VERSION 5.8 ;
BUSBITCHARS "[]" ;
DIVIDERCHAR "/" ;
UNITS
    DATABASE MICRONS 1000 ;
END UNITS

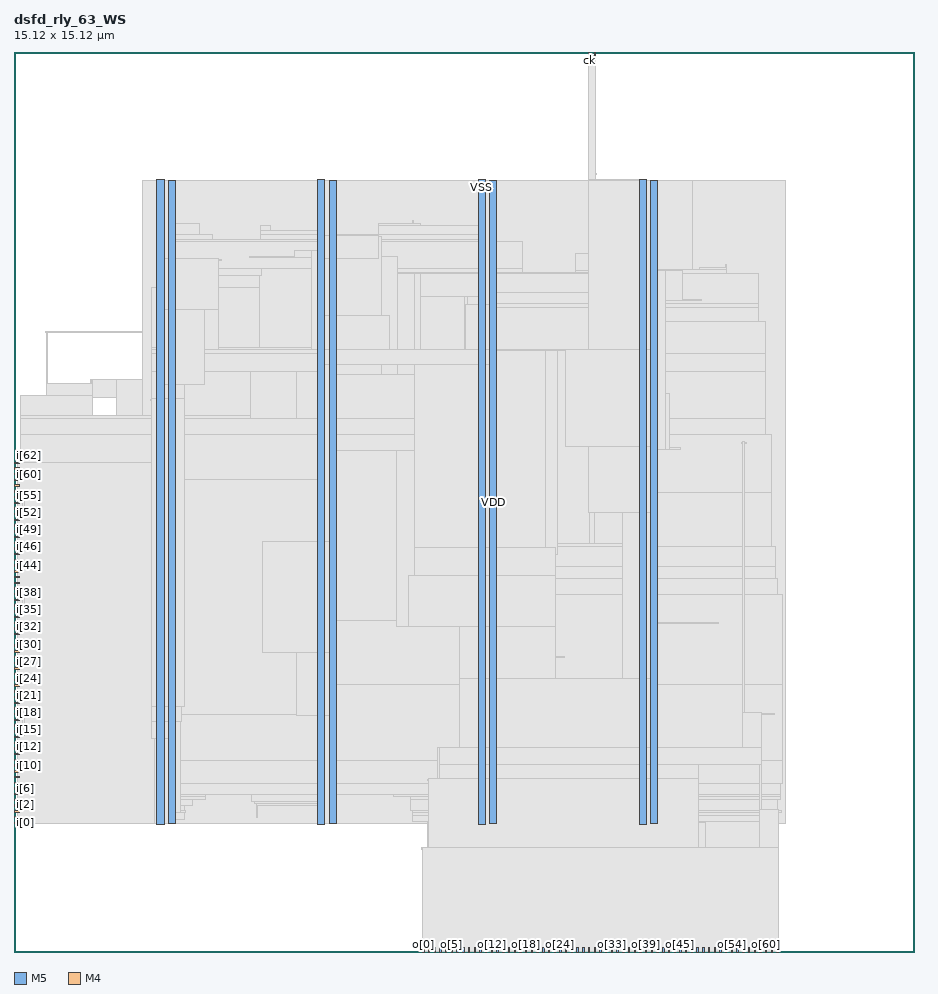
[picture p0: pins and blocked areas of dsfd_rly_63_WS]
MACRO dsfd_rly_63_WS
  FOREIGN dsfd_rly_63_WS 0 0 ;
  CLASS BLOCK ;
  SIZE 15.12 BY 15.12 ;
  PIN ck
    DIRECTION INPUT ;
    USE SIGNAL ;
    PORT
      LAYER M5 ;
        RECT  9.648 15.036 9.672 15.12 ;
    END
  END ck
  PIN i[0]
    DIRECTION INPUT ;
    USE SIGNAL ;
    PORT
      LAYER M4 ;
        RECT  0 2.16 0.084 2.184 ;
    END
  END i[0]
  PIN i[10]
    DIRECTION INPUT ;
    USE SIGNAL ;
    PORT
      LAYER M4 ;
        RECT  0 3.12 0.084 3.144 ;
    END
  END i[10]
  PIN i[11]
    DIRECTION INPUT ;
    USE SIGNAL ;
    PORT
      LAYER M4 ;
        RECT  0 3.216 0.084 3.24 ;
    END
  END i[11]
  PIN i[12]
    DIRECTION INPUT ;
    USE SIGNAL ;
    PORT
      LAYER M4 ;
        RECT  0 3.312 0.084 3.336 ;
    END
  END i[12]
  PIN i[13]
    DIRECTION INPUT ;
    USE SIGNAL ;
    PORT
      LAYER M4 ;
        RECT  0 3.408 0.084 3.432 ;
    END
  END i[13]
  PIN i[14]
    DIRECTION INPUT ;
    USE SIGNAL ;
    PORT
      LAYER M4 ;
        RECT  0 3.504 0.084 3.528 ;
    END
  END i[14]
  PIN i[15]
    DIRECTION INPUT ;
    USE SIGNAL ;
    PORT
      LAYER M4 ;
        RECT  0 3.6 0.084 3.624 ;
    END
  END i[15]
  PIN i[16]
    DIRECTION INPUT ;
    USE SIGNAL ;
    PORT
      LAYER M4 ;
        RECT  0 3.696 0.084 3.72 ;
    END
  END i[16]
  PIN i[17]
    DIRECTION INPUT ;
    USE SIGNAL ;
    PORT
      LAYER M4 ;
        RECT  0 3.792 0.084 3.816 ;
    END
  END i[17]
  PIN i[18]
    DIRECTION INPUT ;
    USE SIGNAL ;
    PORT
      LAYER M4 ;
        RECT  0 3.888 0.084 3.912 ;
    END
  END i[18]
  PIN i[19]
    DIRECTION INPUT ;
    USE SIGNAL ;
    PORT
      LAYER M4 ;
        RECT  0 3.984 0.084 4.008 ;
    END
  END i[19]
  PIN i[1]
    DIRECTION INPUT ;
    USE SIGNAL ;
    PORT
      LAYER M4 ;
        RECT  0 2.256 0.084 2.28 ;
    END
  END i[1]
  PIN i[20]
    DIRECTION INPUT ;
    USE SIGNAL ;
    PORT
      LAYER M4 ;
        RECT  0 4.08 0.084 4.104 ;
    END
  END i[20]
  PIN i[21]
    DIRECTION INPUT ;
    USE SIGNAL ;
    PORT
      LAYER M4 ;
        RECT  0 4.176 0.084 4.2 ;
    END
  END i[21]
  PIN i[22]
    DIRECTION INPUT ;
    USE SIGNAL ;
    PORT
      LAYER M4 ;
        RECT  0 4.272 0.084 4.296 ;
    END
  END i[22]
  PIN i[23]
    DIRECTION INPUT ;
    USE SIGNAL ;
    PORT
      LAYER M4 ;
        RECT  0 4.368 0.084 4.392 ;
    END
  END i[23]
  PIN i[24]
    DIRECTION INPUT ;
    USE SIGNAL ;
    PORT
      LAYER M4 ;
        RECT  0 4.464 0.084 4.488 ;
    END
  END i[24]
  PIN i[25]
    DIRECTION INPUT ;
    USE SIGNAL ;
    PORT
      LAYER M4 ;
        RECT  0 4.56 0.084 4.584 ;
    END
  END i[25]
  PIN i[26]
    DIRECTION INPUT ;
    USE SIGNAL ;
    PORT
      LAYER M4 ;
        RECT  0 4.656 0.084 4.68 ;
    END
  END i[26]
  PIN i[27]
    DIRECTION INPUT ;
    USE SIGNAL ;
    PORT
      LAYER M4 ;
        RECT  0 4.752 0.084 4.776 ;
    END
  END i[27]
  PIN i[28]
    DIRECTION INPUT ;
    USE SIGNAL ;
    PORT
      LAYER M4 ;
        RECT  0 4.848 0.084 4.872 ;
    END
  END i[28]
  PIN i[29]
    DIRECTION INPUT ;
    USE SIGNAL ;
    PORT
      LAYER M4 ;
        RECT  0 4.944 0.084 4.968 ;
    END
  END i[29]
  PIN i[2]
    DIRECTION INPUT ;
    USE SIGNAL ;
    PORT
      LAYER M4 ;
        RECT  0 2.352 0.084 2.376 ;
    END
  END i[2]
  PIN i[30]
    DIRECTION INPUT ;
    USE SIGNAL ;
    PORT
      LAYER M4 ;
        RECT  0 5.04 0.084 5.064 ;
    END
  END i[30]
  PIN i[31]
    DIRECTION INPUT ;
    USE SIGNAL ;
    PORT
      LAYER M4 ;
        RECT  0 5.136 0.084 5.16 ;
    END
  END i[31]
  PIN i[32]
    DIRECTION INPUT ;
    USE SIGNAL ;
    PORT
      LAYER M4 ;
        RECT  0 5.328 0.084 5.352 ;
    END
  END i[32]
  PIN i[33]
    DIRECTION INPUT ;
    USE SIGNAL ;
    PORT
      LAYER M4 ;
        RECT  0 5.424 0.084 5.448 ;
    END
  END i[33]
  PIN i[34]
    DIRECTION INPUT ;
    USE SIGNAL ;
    PORT
      LAYER M4 ;
        RECT  0 5.52 0.084 5.544 ;
    END
  END i[34]
  PIN i[35]
    DIRECTION INPUT ;
    USE SIGNAL ;
    PORT
      LAYER M4 ;
        RECT  0 5.616 0.084 5.64 ;
    END
  END i[35]
  PIN i[36]
    DIRECTION INPUT ;
    USE SIGNAL ;
    PORT
      LAYER M4 ;
        RECT  0 5.712 0.084 5.736 ;
    END
  END i[36]
  PIN i[37]
    DIRECTION INPUT ;
    USE SIGNAL ;
    PORT
      LAYER M4 ;
        RECT  0 5.808 0.084 5.832 ;
    END
  END i[37]
  PIN i[38]
    DIRECTION INPUT ;
    USE SIGNAL ;
    PORT
      LAYER M4 ;
        RECT  0 5.904 0.084 5.928 ;
    END
  END i[38]
  PIN i[39]
    DIRECTION INPUT ;
    USE SIGNAL ;
    PORT
      LAYER M4 ;
        RECT  0 6 0.084 6.024 ;
    END
  END i[39]
  PIN i[3]
    DIRECTION INPUT ;
    USE SIGNAL ;
    PORT
      LAYER M4 ;
        RECT  0 2.448 0.084 2.472 ;
    END
  END i[3]
  PIN i[40]
    DIRECTION INPUT ;
    USE SIGNAL ;
    PORT
      LAYER M4 ;
        RECT  0 6.096 0.084 6.12 ;
    END
  END i[40]
  PIN i[41]
    DIRECTION INPUT ;
    USE SIGNAL ;
    PORT
      LAYER M4 ;
        RECT  0 6.192 0.084 6.216 ;
    END
  END i[41]
  PIN i[42]
    DIRECTION INPUT ;
    USE SIGNAL ;
    PORT
      LAYER M4 ;
        RECT  0 6.288 0.084 6.312 ;
    END
  END i[42]
  PIN i[43]
    DIRECTION INPUT ;
    USE SIGNAL ;
    PORT
      LAYER M4 ;
        RECT  0 6.384 0.084 6.408 ;
    END
  END i[43]
  PIN i[44]
    DIRECTION INPUT ;
    USE SIGNAL ;
    PORT
      LAYER M4 ;
        RECT  0 6.48 0.084 6.504 ;
    END
  END i[44]
  PIN i[45]
    DIRECTION INPUT ;
    USE SIGNAL ;
    PORT
      LAYER M4 ;
        RECT  0 6.576 0.084 6.6 ;
    END
  END i[45]
  PIN i[46]
    DIRECTION INPUT ;
    USE SIGNAL ;
    PORT
      LAYER M4 ;
        RECT  0 6.672 0.084 6.696 ;
    END
  END i[46]
  PIN i[47]
    DIRECTION INPUT ;
    USE SIGNAL ;
    PORT
      LAYER M4 ;
        RECT  0 6.768 0.084 6.792 ;
    END
  END i[47]
  PIN i[48]
    DIRECTION INPUT ;
    USE SIGNAL ;
    PORT
      LAYER M4 ;
        RECT  0 6.864 0.084 6.888 ;
    END
  END i[48]
  PIN i[49]
    DIRECTION INPUT ;
    USE SIGNAL ;
    PORT
      LAYER M4 ;
        RECT  0 6.96 0.084 6.984 ;
    END
  END i[49]
  PIN i[4]
    DIRECTION INPUT ;
    USE SIGNAL ;
    PORT
      LAYER M4 ;
        RECT  0 2.544 0.084 2.568 ;
    END
  END i[4]
  PIN i[50]
    DIRECTION INPUT ;
    USE SIGNAL ;
    PORT
      LAYER M4 ;
        RECT  0 7.056 0.084 7.08 ;
    END
  END i[50]
  PIN i[51]
    DIRECTION INPUT ;
    USE SIGNAL ;
    PORT
      LAYER M4 ;
        RECT  0 7.152 0.084 7.176 ;
    END
  END i[51]
  PIN i[52]
    DIRECTION INPUT ;
    USE SIGNAL ;
    PORT
      LAYER M4 ;
        RECT  0 7.248 0.084 7.272 ;
    END
  END i[52]
  PIN i[53]
    DIRECTION INPUT ;
    USE SIGNAL ;
    PORT
      LAYER M4 ;
        RECT  0 7.344 0.084 7.368 ;
    END
  END i[53]
  PIN i[54]
    DIRECTION INPUT ;
    USE SIGNAL ;
    PORT
      LAYER M4 ;
        RECT  0 7.44 0.084 7.464 ;
    END
  END i[54]
  PIN i[55]
    DIRECTION INPUT ;
    USE SIGNAL ;
    PORT
      LAYER M4 ;
        RECT  0 7.536 0.084 7.56 ;
    END
  END i[55]
  PIN i[56]
    DIRECTION INPUT ;
    USE SIGNAL ;
    PORT
      LAYER M4 ;
        RECT  0 7.632 0.084 7.656 ;
    END
  END i[56]
  PIN i[57]
    DIRECTION INPUT ;
    USE SIGNAL ;
    PORT
      LAYER M4 ;
        RECT  0 7.728 0.084 7.752 ;
    END
  END i[57]
  PIN i[58]
    DIRECTION INPUT ;
    USE SIGNAL ;
    PORT
      LAYER M4 ;
        RECT  0 7.824 0.084 7.848 ;
    END
  END i[58]
  PIN i[59]
    DIRECTION INPUT ;
    USE SIGNAL ;
    PORT
      LAYER M4 ;
        RECT  0 7.92 0.084 7.944 ;
    END
  END i[59]
  PIN i[5]
    DIRECTION INPUT ;
    USE SIGNAL ;
    PORT
      LAYER M4 ;
        RECT  0 2.64 0.084 2.664 ;
    END
  END i[5]
  PIN i[60]
    DIRECTION INPUT ;
    USE SIGNAL ;
    PORT
      LAYER M4 ;
        RECT  0 8.016 0.084 8.04 ;
    END
  END i[60]
  PIN i[61]
    DIRECTION INPUT ;
    USE SIGNAL ;
    PORT
      LAYER M4 ;
        RECT  0 8.112 0.084 8.136 ;
    END
  END i[61]
  PIN i[62]
    DIRECTION INPUT ;
    USE SIGNAL ;
    PORT
      LAYER M4 ;
        RECT  0 8.208 0.084 8.232 ;
    END
  END i[62]
  PIN i[6]
    DIRECTION INPUT ;
    USE SIGNAL ;
    PORT
      LAYER M4 ;
        RECT  0 2.736 0.084 2.76 ;
    END
  END i[6]
  PIN i[7]
    DIRECTION INPUT ;
    USE SIGNAL ;
    PORT
      LAYER M4 ;
        RECT  0 2.832 0.084 2.856 ;
    END
  END i[7]
  PIN i[8]
    DIRECTION INPUT ;
    USE SIGNAL ;
    PORT
      LAYER M4 ;
        RECT  0 2.928 0.084 2.952 ;
    END
  END i[8]
  PIN i[9]
    DIRECTION INPUT ;
    USE SIGNAL ;
    PORT
      LAYER M4 ;
        RECT  0 3.024 0.084 3.048 ;
    END
  END i[9]
  PIN o[0]
    DIRECTION OUTPUT ;
    USE SIGNAL ;
    PORT
      LAYER M5 ;
        RECT  6.864 0 6.888 0.084 ;
    END
  END o[0]
  PIN o[10]
    DIRECTION OUTPUT ;
    USE SIGNAL ;
    PORT
      LAYER M5 ;
        RECT  7.824 0 7.848 0.084 ;
    END
  END o[10]
  PIN o[11]
    DIRECTION OUTPUT ;
    USE SIGNAL ;
    PORT
      LAYER M5 ;
        RECT  7.92 0 7.944 0.084 ;
    END
  END o[11]
  PIN o[12]
    DIRECTION OUTPUT ;
    USE SIGNAL ;
    PORT
      LAYER M5 ;
        RECT  8.016 0 8.04 0.084 ;
    END
  END o[12]
  PIN o[13]
    DIRECTION OUTPUT ;
    USE SIGNAL ;
    PORT
      LAYER M5 ;
        RECT  8.112 0 8.136 0.084 ;
    END
  END o[13]
  PIN o[14]
    DIRECTION OUTPUT ;
    USE SIGNAL ;
    PORT
      LAYER M5 ;
        RECT  8.208 0 8.232 0.084 ;
    END
  END o[14]
  PIN o[15]
    DIRECTION OUTPUT ;
    USE SIGNAL ;
    PORT
      LAYER M5 ;
        RECT  8.304 0 8.328 0.084 ;
    END
  END o[15]
  PIN o[16]
    DIRECTION OUTPUT ;
    USE SIGNAL ;
    PORT
      LAYER M5 ;
        RECT  8.4 0 8.424 0.084 ;
    END
  END o[16]
  PIN o[17]
    DIRECTION OUTPUT ;
    USE SIGNAL ;
    PORT
      LAYER M5 ;
        RECT  8.496 0 8.52 0.084 ;
    END
  END o[17]
  PIN o[18]
    DIRECTION OUTPUT ;
    USE SIGNAL ;
    PORT
      LAYER M5 ;
        RECT  8.592 0 8.616 0.084 ;
    END
  END o[18]
  PIN o[19]
    DIRECTION OUTPUT ;
    USE SIGNAL ;
    PORT
      LAYER M5 ;
        RECT  8.688 0 8.712 0.084 ;
    END
  END o[19]
  PIN o[1]
    DIRECTION OUTPUT ;
    USE SIGNAL ;
    PORT
      LAYER M5 ;
        RECT  6.96 0 6.984 0.084 ;
    END
  END o[1]
  PIN o[20]
    DIRECTION OUTPUT ;
    USE SIGNAL ;
    PORT
      LAYER M5 ;
        RECT  8.784 0 8.808 0.084 ;
    END
  END o[20]
  PIN o[21]
    DIRECTION OUTPUT ;
    USE SIGNAL ;
    PORT
      LAYER M5 ;
        RECT  8.88 0 8.904 0.084 ;
    END
  END o[21]
  PIN o[22]
    DIRECTION OUTPUT ;
    USE SIGNAL ;
    PORT
      LAYER M5 ;
        RECT  8.976 0 9 0.084 ;
    END
  END o[22]
  PIN o[23]
    DIRECTION OUTPUT ;
    USE SIGNAL ;
    PORT
      LAYER M5 ;
        RECT  9.072 0 9.096 0.084 ;
    END
  END o[23]
  PIN o[24]
    DIRECTION OUTPUT ;
    USE SIGNAL ;
    PORT
      LAYER M5 ;
        RECT  9.168 0 9.192 0.084 ;
    END
  END o[24]
  PIN o[25]
    DIRECTION OUTPUT ;
    USE SIGNAL ;
    PORT
      LAYER M5 ;
        RECT  9.264 0 9.288 0.084 ;
    END
  END o[25]
  PIN o[26]
    DIRECTION OUTPUT ;
    USE SIGNAL ;
    PORT
      LAYER M5 ;
        RECT  9.36 0 9.384 0.084 ;
    END
  END o[26]
  PIN o[27]
    DIRECTION OUTPUT ;
    USE SIGNAL ;
    PORT
      LAYER M5 ;
        RECT  9.456 0 9.48 0.084 ;
    END
  END o[27]
  PIN o[28]
    DIRECTION OUTPUT ;
    USE SIGNAL ;
    PORT
      LAYER M5 ;
        RECT  9.552 0 9.576 0.084 ;
    END
  END o[28]
  PIN o[29]
    DIRECTION OUTPUT ;
    USE SIGNAL ;
    PORT
      LAYER M5 ;
        RECT  9.648 0 9.672 0.084 ;
    END
  END o[29]
  PIN o[2]
    DIRECTION OUTPUT ;
    USE SIGNAL ;
    PORT
      LAYER M5 ;
        RECT  7.056 0 7.08 0.084 ;
    END
  END o[2]
  PIN o[30]
    DIRECTION OUTPUT ;
    USE SIGNAL ;
    PORT
      LAYER M5 ;
        RECT  9.744 0 9.768 0.084 ;
    END
  END o[30]
  PIN o[31]
    DIRECTION OUTPUT ;
    USE SIGNAL ;
    PORT
      LAYER M5 ;
        RECT  9.84 0 9.864 0.084 ;
    END
  END o[31]
  PIN o[32]
    DIRECTION OUTPUT ;
    USE SIGNAL ;
    PORT
      LAYER M5 ;
        RECT  9.936 0 9.96 0.084 ;
    END
  END o[32]
  PIN o[33]
    DIRECTION OUTPUT ;
    USE SIGNAL ;
    PORT
      LAYER M5 ;
        RECT  10.032 0 10.056 0.084 ;
    END
  END o[33]
  PIN o[34]
    DIRECTION OUTPUT ;
    USE SIGNAL ;
    PORT
      LAYER M5 ;
        RECT  10.128 0 10.152 0.084 ;
    END
  END o[34]
  PIN o[35]
    DIRECTION OUTPUT ;
    USE SIGNAL ;
    PORT
      LAYER M5 ;
        RECT  10.224 0 10.248 0.084 ;
    END
  END o[35]
  PIN o[36]
    DIRECTION OUTPUT ;
    USE SIGNAL ;
    PORT
      LAYER M5 ;
        RECT  10.32 0 10.344 0.084 ;
    END
  END o[36]
  PIN o[37]
    DIRECTION OUTPUT ;
    USE SIGNAL ;
    PORT
      LAYER M5 ;
        RECT  10.416 0 10.44 0.084 ;
    END
  END o[37]
  PIN o[38]
    DIRECTION OUTPUT ;
    USE SIGNAL ;
    PORT
      LAYER M5 ;
        RECT  10.512 0 10.536 0.084 ;
    END
  END o[38]
  PIN o[39]
    DIRECTION OUTPUT ;
    USE SIGNAL ;
    PORT
      LAYER M5 ;
        RECT  10.608 0 10.632 0.084 ;
    END
  END o[39]
  PIN o[3]
    DIRECTION OUTPUT ;
    USE SIGNAL ;
    PORT
      LAYER M5 ;
        RECT  7.152 0 7.176 0.084 ;
    END
  END o[3]
  PIN o[40]
    DIRECTION OUTPUT ;
    USE SIGNAL ;
    PORT
      LAYER M5 ;
        RECT  10.704 0 10.728 0.084 ;
    END
  END o[40]
  PIN o[41]
    DIRECTION OUTPUT ;
    USE SIGNAL ;
    PORT
      LAYER M5 ;
        RECT  10.8 0 10.824 0.084 ;
    END
  END o[41]
  PIN o[42]
    DIRECTION OUTPUT ;
    USE SIGNAL ;
    PORT
      LAYER M5 ;
        RECT  10.896 0 10.92 0.084 ;
    END
  END o[42]
  PIN o[43]
    DIRECTION OUTPUT ;
    USE SIGNAL ;
    PORT
      LAYER M5 ;
        RECT  10.992 0 11.016 0.084 ;
    END
  END o[43]
  PIN o[44]
    DIRECTION OUTPUT ;
    USE SIGNAL ;
    PORT
      LAYER M5 ;
        RECT  11.088 0 11.112 0.084 ;
    END
  END o[44]
  PIN o[45]
    DIRECTION OUTPUT ;
    USE SIGNAL ;
    PORT
      LAYER M5 ;
        RECT  11.184 0 11.208 0.084 ;
    END
  END o[45]
  PIN o[46]
    DIRECTION OUTPUT ;
    USE SIGNAL ;
    PORT
      LAYER M5 ;
        RECT  11.28 0 11.304 0.084 ;
    END
  END o[46]
  PIN o[47]
    DIRECTION OUTPUT ;
    USE SIGNAL ;
    PORT
      LAYER M5 ;
        RECT  11.376 0 11.4 0.084 ;
    END
  END o[47]
  PIN o[48]
    DIRECTION OUTPUT ;
    USE SIGNAL ;
    PORT
      LAYER M5 ;
        RECT  11.472 0 11.496 0.084 ;
    END
  END o[48]
  PIN o[49]
    DIRECTION OUTPUT ;
    USE SIGNAL ;
    PORT
      LAYER M5 ;
        RECT  11.568 0 11.592 0.084 ;
    END
  END o[49]
  PIN o[4]
    DIRECTION OUTPUT ;
    USE SIGNAL ;
    PORT
      LAYER M5 ;
        RECT  7.248 0 7.272 0.084 ;
    END
  END o[4]
  PIN o[50]
    DIRECTION OUTPUT ;
    USE SIGNAL ;
    PORT
      LAYER M5 ;
        RECT  11.664 0 11.688 0.084 ;
    END
  END o[50]
  PIN o[51]
    DIRECTION OUTPUT ;
    USE SIGNAL ;
    PORT
      LAYER M5 ;
        RECT  11.76 0 11.784 0.084 ;
    END
  END o[51]
  PIN o[52]
    DIRECTION OUTPUT ;
    USE SIGNAL ;
    PORT
      LAYER M5 ;
        RECT  11.856 0 11.88 0.084 ;
    END
  END o[52]
  PIN o[53]
    DIRECTION OUTPUT ;
    USE SIGNAL ;
    PORT
      LAYER M5 ;
        RECT  11.952 0 11.976 0.084 ;
    END
  END o[53]
  PIN o[54]
    DIRECTION OUTPUT ;
    USE SIGNAL ;
    PORT
      LAYER M5 ;
        RECT  12.048 0 12.072 0.084 ;
    END
  END o[54]
  PIN o[55]
    DIRECTION OUTPUT ;
    USE SIGNAL ;
    PORT
      LAYER M5 ;
        RECT  12.144 0 12.168 0.084 ;
    END
  END o[55]
  PIN o[56]
    DIRECTION OUTPUT ;
    USE SIGNAL ;
    PORT
      LAYER M5 ;
        RECT  12.24 0 12.264 0.084 ;
    END
  END o[56]
  PIN o[57]
    DIRECTION OUTPUT ;
    USE SIGNAL ;
    PORT
      LAYER M5 ;
        RECT  12.336 0 12.36 0.084 ;
    END
  END o[57]
  PIN o[58]
    DIRECTION OUTPUT ;
    USE SIGNAL ;
    PORT
      LAYER M5 ;
        RECT  12.432 0 12.456 0.084 ;
    END
  END o[58]
  PIN o[59]
    DIRECTION OUTPUT ;
    USE SIGNAL ;
    PORT
      LAYER M5 ;
        RECT  12.528 0 12.552 0.084 ;
    END
  END o[59]
  PIN o[5]
    DIRECTION OUTPUT ;
    USE SIGNAL ;
    PORT
      LAYER M5 ;
        RECT  7.344 0 7.368 0.084 ;
    END
  END o[5]
  PIN o[60]
    DIRECTION OUTPUT ;
    USE SIGNAL ;
    PORT
      LAYER M5 ;
        RECT  12.624 0 12.648 0.084 ;
    END
  END o[60]
  PIN o[61]
    DIRECTION OUTPUT ;
    USE SIGNAL ;
    PORT
      LAYER M5 ;
        RECT  12.72 0 12.744 0.084 ;
    END
  END o[61]
  PIN o[62]
    DIRECTION OUTPUT ;
    USE SIGNAL ;
    PORT
      LAYER M5 ;
        RECT  12.816 0 12.84 0.084 ;
    END
  END o[62]
  PIN o[6]
    DIRECTION OUTPUT ;
    USE SIGNAL ;
    PORT
      LAYER M5 ;
        RECT  7.44 0 7.464 0.084 ;
    END
  END o[6]
  PIN o[7]
    DIRECTION OUTPUT ;
    USE SIGNAL ;
    PORT
      LAYER M5 ;
        RECT  7.536 0 7.56 0.084 ;
    END
  END o[7]
  PIN o[8]
    DIRECTION OUTPUT ;
    USE SIGNAL ;
    PORT
      LAYER M5 ;
        RECT  7.632 0 7.656 0.084 ;
    END
  END o[8]
  PIN o[9]
    DIRECTION OUTPUT ;
    USE SIGNAL ;
    PORT
      LAYER M5 ;
        RECT  7.728 0 7.752 0.084 ;
    END
  END o[9]
  PIN rs
    DIRECTION INPUT ;
    USE SIGNAL ;
    PORT
      LAYER M5 ;
        RECT  9.744 15.036 9.768 15.12 ;
    END
  END rs
  PIN VDD
    DIRECTION INOUT ;
    USE POWER ;
    PORT
      LAYER M5 ;
        RECT  10.692 2.151 10.812 12.969 ;
        RECT  7.992 2.151 8.112 12.969 ;
        RECT  5.292 2.151 5.412 12.969 ;
        RECT  2.592 2.151 2.712 12.969 ;
    END
  END VDD
  PIN VSS
    DIRECTION INOUT ;
    USE GROUND ;
    PORT
      LAYER M5 ;
        RECT  10.5 2.137 10.62 12.983 ;
        RECT  7.8 2.137 7.92 12.983 ;
        RECT  5.1 2.137 5.22 12.983 ;
        RECT  2.4 2.137 2.52 12.983 ;
    END
  END VSS
  OBS
    LAYER RVTN ;
     RECT  2.16 2.16 12.96 2.295 ;
     RECT  2.16 2.565 12.96 2.835 ;
     RECT  2.16 3.105 12.96 3.375 ;
     RECT  2.16 3.645 12.96 3.915 ;
     RECT  2.16 4.185 12.96 4.455 ;
     RECT  2.16 4.725 12.96 4.995 ;
     RECT  2.16 5.265 12.96 5.535 ;
     RECT  2.16 5.805 12.96 6.075 ;
     RECT  2.16 6.345 12.96 6.615 ;
     RECT  2.16 6.885 12.96 7.155 ;
     RECT  2.16 7.425 12.96 7.695 ;
     RECT  2.16 7.965 12.96 8.235 ;
     RECT  2.16 8.505 12.96 8.775 ;
     RECT  2.16 9.045 12.96 9.315 ;
     RECT  2.16 9.585 12.96 9.855 ;
     RECT  2.16 10.125 12.96 10.395 ;
     RECT  2.16 10.665 12.96 10.935 ;
     RECT  2.16 11.205 12.96 11.475 ;
     RECT  2.16 11.745 12.96 12.015 ;
     RECT  2.16 12.285 12.96 12.555 ;
     RECT  2.16 12.825 12.96 12.96 ;
    LAYER RVTP ;
     RECT  2.16 2.295 12.96 2.565 ;
     RECT  2.16 2.835 12.96 3.105 ;
     RECT  2.16 3.375 12.96 3.645 ;
     RECT  2.16 3.915 12.96 4.185 ;
     RECT  2.16 4.455 12.96 4.725 ;
     RECT  2.16 4.995 12.96 5.265 ;
     RECT  2.16 5.535 12.96 5.805 ;
     RECT  2.16 6.075 12.96 6.345 ;
     RECT  2.16 6.615 12.96 6.885 ;
     RECT  2.16 7.155 12.96 7.425 ;
     RECT  2.16 7.695 12.96 7.965 ;
     RECT  2.16 8.235 12.96 8.505 ;
     RECT  2.16 8.775 12.96 9.045 ;
     RECT  2.16 9.315 12.96 9.585 ;
     RECT  2.16 9.855 12.96 10.125 ;
     RECT  2.16 10.395 12.96 10.665 ;
     RECT  2.16 10.935 12.96 11.205 ;
     RECT  2.16 11.475 12.96 11.745 ;
     RECT  2.16 12.015 12.96 12.285 ;
     RECT  2.16 12.555 12.96 12.825 ;
    LAYER M1 ;
     RECT  2.16 2.151 12.96 12.969 ;
    LAYER M2 ;
     RECT  0.175 8.442 0.211 8.46 ;
     RECT  0.139 6.12 0.319 6.678 ;
     RECT  0.247 5.238 0.535 5.256 ;
     RECT  0.319 6.12 0.563 7.254 ;
     RECT  0.211 3.96 0.823 3.978 ;
     RECT  0.103 9.324 1.147 9.342 ;
     RECT  1.147 9.324 1.291 9.54 ;
     RECT  0.211 8.01 1.723 8.46 ;
     RECT  1.291 9.324 1.723 9.612 ;
     RECT  0.823 3.96 2.119 4.446 ;
     RECT  2.119 3.96 2.16 4.482 ;
     RECT  0.535 5.238 2.16 5.328 ;
     RECT  0.563 6.12 2.16 6.408 ;
     RECT  0.563 7.236 2.16 7.254 ;
     RECT  1.723 8.01 2.16 9.612 ;
     RECT  0.535 10.404 2.16 10.422 ;
     RECT  2.16 2.151 10.723 12.969 ;
     RECT  10.723 2.106 11.399 12.969 ;
     RECT  11.399 2.151 12.96 12.969 ;
    LAYER M3 ;
     RECT  10.872 0.091 11.682 0.139 ;
     RECT  12.672 0.091 12.69 0.139 ;
     RECT  7.488 0.091 7.506 0.571 ;
     RECT  8.352 0.091 8.658 0.571 ;
     RECT  9.612 0.091 9.63 0.571 ;
     RECT  10.872 0.139 12.69 0.571 ;
     RECT  9.612 0.571 12.69 0.619 ;
     RECT  7.488 0.571 8.658 1.147 ;
     RECT  7.128 1.147 8.658 1.723 ;
     RECT  9.432 0.619 12.69 1.723 ;
     RECT  2.415 2.143 2.505 2.155 ;
     RECT  2.304 2.155 2.505 2.191 ;
     RECT  6.948 1.723 12.69 2.191 ;
     RECT  2.304 2.191 2.61 2.227 ;
     RECT  6.696 2.191 12.69 2.299 ;
     RECT  6.696 2.299 12.762 2.347 ;
     RECT  6.696 2.347 12.834 2.371 ;
     RECT  5.115 2.143 5.205 2.413 ;
     RECT  2.304 2.227 2.862 2.461 ;
     RECT  4.068 2.263 4.086 2.461 ;
     RECT  5.115 2.413 5.397 2.461 ;
     RECT  4.068 2.461 5.397 2.497 ;
     RECT  4.032 2.497 5.397 2.533 ;
     RECT  2.304 2.461 3.006 2.569 ;
     RECT  6.66 2.371 12.834 2.569 ;
     RECT  2.304 2.569 3.222 2.605 ;
     RECT  6.66 2.569 12.87 2.605 ;
     RECT  2.268 2.605 3.222 2.641 ;
     RECT  3.996 2.533 5.397 2.641 ;
     RECT  6.372 2.605 12.87 2.641 ;
     RECT  2.268 2.641 12.87 2.839 ;
     RECT  2.268 2.839 12.906 3.211 ;
     RECT  0.828 2.827 0.846 3.787 ;
     RECT  0.324 3.787 0.846 3.955 ;
     RECT  0.216 3.955 0.846 3.979 ;
     RECT  0.144 3.979 0.846 4.451 ;
     RECT  2.124 3.211 12.906 4.487 ;
     RECT  0.144 4.451 0.198 4.939 ;
     RECT  0.108 4.939 0.198 5.233 ;
     RECT  0.108 5.233 0.27 5.305 ;
     RECT  2.232 4.487 12.906 5.999 ;
     RECT  0.108 5.305 0.558 6.091 ;
     RECT  0.108 6.091 1.17 6.221 ;
     RECT  2.232 5.999 12.834 6.269 ;
     RECT  2.232 6.269 12.798 6.475 ;
     RECT  2.196 6.475 12.798 6.809 ;
     RECT  0.108 6.221 0.558 7.243 ;
     RECT  1.296 6.955 1.314 7.243 ;
     RECT  0.108 7.243 1.314 7.723 ;
     RECT  2.196 6.809 12.726 7.723 ;
     RECT  0.108 7.723 12.726 8.699 ;
     RECT  0.108 8.699 12.618 8.969 ;
     RECT  0.108 8.969 3.978 9.005 ;
     RECT  0.108 9.005 1.314 9.347 ;
     RECT  0.54 9.347 1.314 9.545 ;
     RECT  1.296 9.545 1.314 9.617 ;
     RECT  2.304 9.005 3.978 9.751 ;
     RECT  4.752 8.969 12.618 9.751 ;
     RECT  2.304 9.751 12.618 10.049 ;
     RECT  2.304 10.049 9.774 10.121 ;
     RECT  2.304 10.121 4.194 10.163 ;
     RECT  0.54 9.545 0.558 10.427 ;
     RECT  10.515 10.049 12.618 10.589 ;
     RECT  5.115 10.121 9.774 10.831 ;
     RECT  10.515 10.589 12.51 10.831 ;
     RECT  5.115 10.831 12.51 10.891 ;
     RECT  2.304 10.163 4.122 11.165 ;
     RECT  2.415 11.165 4.122 11.371 ;
     RECT  5.004 10.891 12.51 11.399 ;
     RECT  5.004 11.399 9.774 11.408 ;
     RECT  9.432 11.408 9.774 11.453 ;
     RECT  10.515 11.399 11.97 11.471 ;
     RECT  2.415 11.371 4.158 11.479 ;
     RECT  5.004 11.408 8.55 11.479 ;
     RECT  11.52 11.471 11.97 11.507 ;
     RECT  11.952 11.507 11.97 11.543 ;
     RECT  9.432 11.453 9.666 11.741 ;
     RECT  2.415 11.479 8.55 11.939 ;
     RECT  2.415 11.939 8.097 11.975 ;
     RECT  2.415 11.975 3.33 12.047 ;
     RECT  4.14 11.975 8.097 12.047 ;
     RECT  4.14 12.047 5.397 12.119 ;
     RECT  4.14 12.119 4.302 12.209 ;
     RECT  6.12 12.047 8.097 12.209 ;
     RECT  2.415 12.047 3.114 12.245 ;
     RECT  6.12 12.209 6.822 12.245 ;
     RECT  6.696 12.245 6.714 12.281 ;
     RECT  9.648 11.741 9.666 12.325 ;
     RECT  10.515 11.471 10.797 12.325 ;
     RECT  9.648 12.325 10.797 12.389 ;
     RECT  2.415 12.245 2.697 12.707 ;
     RECT  5.115 12.119 5.397 12.707 ;
     RECT  7.815 12.209 8.097 12.707 ;
     RECT  9.756 12.389 10.797 12.707 ;
     RECT  9.756 12.707 10.605 12.749 ;
     RECT  2.415 12.707 2.505 12.977 ;
     RECT  5.115 12.707 5.205 12.977 ;
     RECT  7.815 12.707 7.905 12.977 ;
     RECT  10.515 12.749 10.605 12.977 ;
     RECT  9.756 12.749 9.774 13.085 ;
    LAYER M4 ;
     RECT  0.06 2.16 2.365 8.232 ;
     RECT  2.293 9.264 2.365 9.288 ;
     RECT  2.365 2.16 2.408 9.288 ;
     RECT  2.408 2.148 2.512 12.972 ;
     RECT  2.512 2.256 2.585 12.702 ;
     RECT  2.585 2.352 2.704 12.702 ;
     RECT  2.704 2.352 2.801 7.944 ;
     RECT  2.801 3.888 2.819 7.944 ;
     RECT  2.704 9.12 2.867 11.64 ;
     RECT  2.801 2.352 2.873 2.376 ;
     RECT  2.867 9.552 3.203 11.64 ;
     RECT  3.203 10.128 3.443 11.64 ;
     RECT  3.443 11.616 3.485 11.64 ;
     RECT  3.949 11.664 4.705 11.688 ;
     RECT  3.443 10.128 4.993 10.152 ;
     RECT  4.705 11.664 4.993 11.784 ;
     RECT  2.819 3.984 5.108 7.944 ;
     RECT  4.993 10.128 5.108 11.784 ;
     RECT  5.108 2.148 5.212 12.972 ;
     RECT  5.212 2.418 5.404 12.702 ;
     RECT  5.404 9.696 6.172 12.024 ;
     RECT  5.404 5.568 6.433 8.424 ;
     RECT  6.172 9.696 6.437 11.688 ;
     RECT  6.433 5.472 6.721 8.424 ;
     RECT  6.437 9.696 6.721 11.4 ;
     RECT  6.721 5.472 6.833 11.4 ;
     RECT  6.853 1.728 7.045 1.752 ;
     RECT  6.949 2.88 7.109 2.904 ;
     RECT  7.045 1.152 7.3 1.752 ;
     RECT  7.109 2.88 7.477 3.432 ;
     RECT  7.3 1.152 7.525 1.8 ;
     RECT  7.477 2.832 7.525 3.432 ;
     RECT  6.833 5.472 7.573 11.016 ;
     RECT  7.573 4.944 7.621 11.016 ;
     RECT  7.525 1.152 7.808 3.432 ;
     RECT  7.621 4.56 7.808 11.016 ;
     RECT  7.808 1.152 7.912 12.972 ;
     RECT  7.429 0.096 8.101 0.12 ;
     RECT  7.912 1.152 8.101 12.702 ;
     RECT  8.101 0.096 8.104 12.702 ;
     RECT  8.104 0.096 8.165 1.752 ;
     RECT  8.104 2.784 8.749 2.904 ;
     RECT  8.104 4.944 8.921 10.104 ;
     RECT  8.921 4.944 9.065 5.496 ;
     RECT  8.921 6.672 9.137 10.104 ;
     RECT  9.065 4.944 9.245 4.968 ;
     RECT  8.165 0.096 9.349 0.6 ;
     RECT  8.165 1.728 9.565 1.752 ;
     RECT  9.349 0.096 9.641 0.648 ;
     RECT  9.641 0.144 9.673 0.648 ;
     RECT  9.565 1.728 9.673 2.28 ;
     RECT  9.137 6.864 9.673 10.104 ;
     RECT  8.104 11.088 9.673 11.4 ;
     RECT  9.673 6.864 9.745 11.4 ;
     RECT  9.673 0.144 9.779 2.28 ;
     RECT  9.701 13.056 9.785 13.08 ;
     RECT  9.845 4.56 10.097 4.584 ;
     RECT  9.779 1.728 10.172 2.28 ;
     RECT  9.779 0.144 10.181 0.6 ;
     RECT  9.745 6.864 10.249 11.448 ;
     RECT  10.249 6.048 10.261 11.448 ;
     RECT  10.097 3.984 10.268 4.584 ;
     RECT  10.261 5.76 10.268 11.448 ;
     RECT  10.181 0.144 10.403 0.264 ;
     RECT  10.172 1.728 10.508 2.664 ;
     RECT  10.268 3.984 10.508 11.448 ;
     RECT  10.508 1.728 10.612 12.972 ;
     RECT  10.403 0.144 10.693 0.168 ;
     RECT  10.612 1.728 10.804 12.702 ;
     RECT  10.804 8.448 10.937 11.448 ;
     RECT  10.937 8.448 11.009 9.384 ;
     RECT  11.009 8.448 11.189 8.472 ;
     RECT  10.937 10.944 11.225 11.448 ;
     RECT  10.804 1.728 11.411 2.28 ;
     RECT  11.225 10.944 11.549 10.968 ;
     RECT  11.411 1.728 11.621 2.184 ;
     RECT  10.693 0.096 11.689 0.168 ;
     RECT  10.804 3.408 11.833 3.432 ;
     RECT  10.804 5.52 11.837 5.544 ;
     RECT  11.689 0.096 12.005 0.552 ;
     RECT  11.621 1.728 12.092 1.752 ;
     RECT  11.833 3.168 12.275 3.432 ;
     RECT  12.221 8.544 12.305 8.568 ;
     RECT  12.005 0.096 12.449 0.6 ;
     RECT  12.092 1.68 12.485 1.752 ;
     RECT  12.572 1.104 12.659 1.128 ;
     RECT  12.449 0.096 12.701 0.12 ;
     RECT  12.689 2.304 12.773 2.376 ;
     RECT  12.517 3.984 12.773 4.008 ;
     RECT  12.773 2.352 12.889 2.376 ;
    LAYER M5 ;
     RECT  6.864 0.016 12.84 1.763 ;
     RECT  2.4 2.137 2.52 2.151 ;
     RECT  5.1 2.137 5.22 2.151 ;
     RECT  12.528 1.763 12.84 2.387 ;
     RECT  6.96 1.763 11.496 2.915 ;
     RECT  7.152 2.915 11.496 3.157 ;
     RECT  12.528 2.387 12.552 3.157 ;
     RECT  7.152 3.157 12.552 3.443 ;
     RECT  2.4 2.151 2.712 3.589 ;
     RECT  2.304 3.589 2.712 3.877 ;
     RECT  0.144 3.637 0.168 3.923 ;
     RECT  5.1 2.151 5.412 3.973 ;
     RECT  12.24 3.443 12.552 4.019 ;
     RECT  2.304 3.877 2.808 4.117 ;
     RECT  7.488 3.443 10.812 4.595 ;
     RECT  4.752 3.973 5.412 5.029 ;
     RECT  7.488 4.595 9.096 5.461 ;
     RECT  0.144 5.845 0.168 6.035 ;
     RECT  6.624 5.461 9.096 6.323 ;
     RECT  6.72 6.323 9.096 6.803 ;
     RECT  4.176 5.029 5.412 6.899 ;
     RECT  10.224 4.595 10.812 7.381 ;
     RECT  0.144 7.477 0.168 7.667 ;
     RECT  9.648 7.381 10.812 8.485 ;
     RECT  12.24 4.019 12.264 8.579 ;
     RECT  2.304 4.117 2.856 9.299 ;
     RECT  2.4 9.299 2.856 9.541 ;
     RECT  5.1 6.899 5.412 9.877 ;
     RECT  6.72 6.803 8.112 9.877 ;
     RECT  5.1 9.877 8.112 10.115 ;
     RECT  9.264 8.485 10.812 10.115 ;
     RECT  5.1 10.115 6.312 10.691 ;
     RECT  2.4 9.541 3.192 10.789 ;
     RECT  7.584 10.115 8.112 10.883 ;
     RECT  2.4 10.789 3.432 11.651 ;
     RECT  5.1 10.691 5.412 11.653 ;
     RECT  5.1 11.653 6.12 12.035 ;
     RECT  2.4 11.651 2.712 12.969 ;
     RECT  5.1 12.035 5.412 12.969 ;
     RECT  7.8 10.883 8.112 12.969 ;
     RECT  9.648 10.115 10.812 12.969 ;
     RECT  2.4 12.969 2.52 12.983 ;
     RECT  5.1 12.969 5.22 12.983 ;
     RECT  7.8 12.969 7.92 12.983 ;
     RECT  9.648 12.969 10.62 12.983 ;
     RECT  9.648 12.983 9.768 15.056 ;
  END
END dsfd_rly_63_WS
END LIBRARY
